VERSION 5.7 ;
BUSBITCHARS "[]" ;
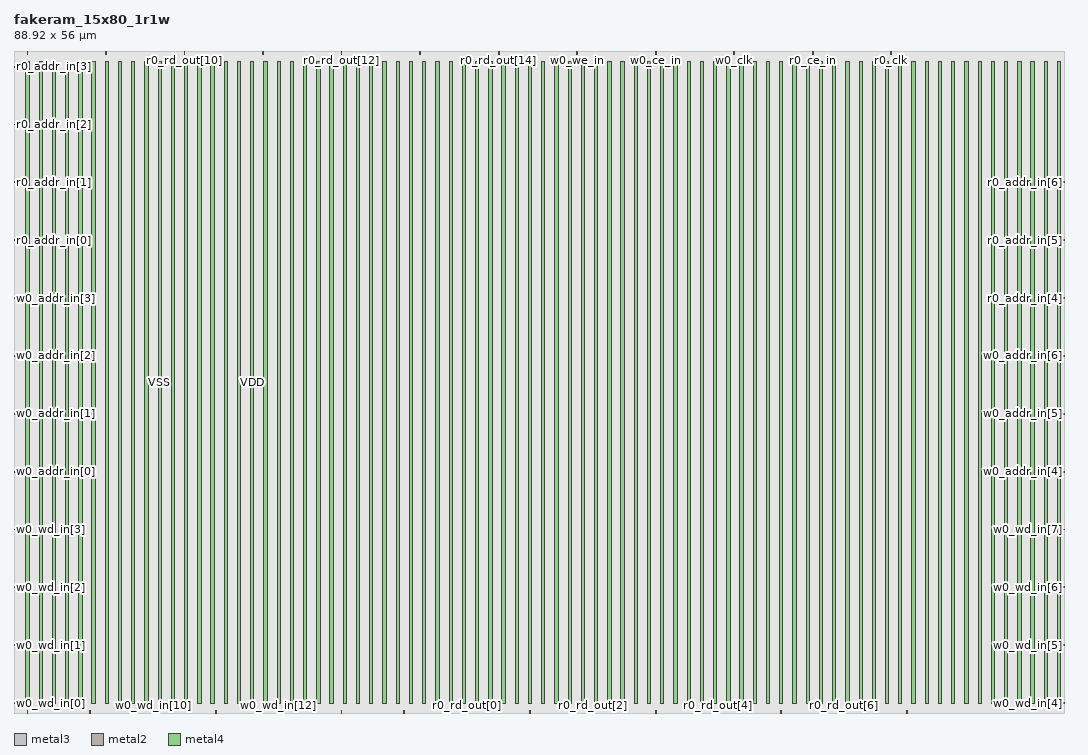
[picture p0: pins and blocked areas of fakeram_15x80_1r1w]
MACRO fakeram_15x80_1r1w
  FOREIGN fakeram_15x80_1r1w 0 0 ;
  SYMMETRY X Y R90 ;
  SIZE 88.920 BY 56.000 ;
  CLASS BLOCK ;
  PIN w0_wd_in[0]
    DIRECTION INPUT ;
    USE SIGNAL ;
    SHAPE ABUTMENT ;
    PORT
      LAYER metal3 ;
      RECT 0.000 0.805 0.210 0.875 ;
    END
  END w0_wd_in[0]
  PIN w0_wd_in[1]
    DIRECTION INPUT ;
    USE SIGNAL ;
    SHAPE ABUTMENT ;
    PORT
      LAYER metal3 ;
      RECT 0.000 5.705 0.210 5.775 ;
    END
  END w0_wd_in[1]
  PIN w0_wd_in[2]
    DIRECTION INPUT ;
    USE SIGNAL ;
    SHAPE ABUTMENT ;
    PORT
      LAYER metal3 ;
      RECT 0.000 10.605 0.210 10.675 ;
    END
  END w0_wd_in[2]
  PIN w0_wd_in[3]
    DIRECTION INPUT ;
    USE SIGNAL ;
    SHAPE ABUTMENT ;
    PORT
      LAYER metal3 ;
      RECT 0.000 15.505 0.210 15.575 ;
    END
  END w0_wd_in[3]
  PIN w0_wd_in[4]
    DIRECTION INPUT ;
    USE SIGNAL ;
    SHAPE ABUTMENT ;
    PORT
      LAYER metal3 ;
      RECT 88.710 0.805 88.920 0.875 ;
    END
  END w0_wd_in[4]
  PIN w0_wd_in[5]
    DIRECTION INPUT ;
    USE SIGNAL ;
    SHAPE ABUTMENT ;
    PORT
      LAYER metal3 ;
      RECT 88.710 5.705 88.920 5.775 ;
    END
  END w0_wd_in[5]
  PIN w0_wd_in[6]
    DIRECTION INPUT ;
    USE SIGNAL ;
    SHAPE ABUTMENT ;
    PORT
      LAYER metal3 ;
      RECT 88.710 10.605 88.920 10.675 ;
    END
  END w0_wd_in[6]
  PIN w0_wd_in[7]
    DIRECTION INPUT ;
    USE SIGNAL ;
    SHAPE ABUTMENT ;
    PORT
      LAYER metal3 ;
      RECT 88.710 15.505 88.920 15.575 ;
    END
  END w0_wd_in[7]
  PIN w0_wd_in[8]
    DIRECTION INPUT ;
    USE SIGNAL ;
    SHAPE ABUTMENT ;
    PORT
      LAYER metal2 ;
      RECT 1.105 0.000 1.175 0.210 ;
    END
  END w0_wd_in[8]
  PIN w0_wd_in[9]
    DIRECTION INPUT ;
    USE SIGNAL ;
    SHAPE ABUTMENT ;
    PORT
      LAYER metal2 ;
      RECT 6.425 0.000 6.495 0.210 ;
    END
  END w0_wd_in[9]
  PIN w0_wd_in[10]
    DIRECTION INPUT ;
    USE SIGNAL ;
    SHAPE ABUTMENT ;
    PORT
      LAYER metal2 ;
      RECT 11.745 0.000 11.815 0.210 ;
    END
  END w0_wd_in[10]
  PIN w0_wd_in[11]
    DIRECTION INPUT ;
    USE SIGNAL ;
    SHAPE ABUTMENT ;
    PORT
      LAYER metal2 ;
      RECT 17.065 0.000 17.135 0.210 ;
    END
  END w0_wd_in[11]
  PIN w0_wd_in[12]
    DIRECTION INPUT ;
    USE SIGNAL ;
    SHAPE ABUTMENT ;
    PORT
      LAYER metal2 ;
      RECT 22.385 0.000 22.455 0.210 ;
    END
  END w0_wd_in[12]
  PIN w0_wd_in[13]
    DIRECTION INPUT ;
    USE SIGNAL ;
    SHAPE ABUTMENT ;
    PORT
      LAYER metal2 ;
      RECT 27.705 0.000 27.775 0.210 ;
    END
  END w0_wd_in[13]
  PIN w0_wd_in[14]
    DIRECTION INPUT ;
    USE SIGNAL ;
    SHAPE ABUTMENT ;
    PORT
      LAYER metal2 ;
      RECT 33.025 0.000 33.095 0.210 ;
    END
  END w0_wd_in[14]
  PIN r0_rd_out[0]
    DIRECTION OUTPUT ;
    USE SIGNAL ;
    SHAPE ABUTMENT ;
    PORT
      LAYER metal2 ;
      RECT 38.345 0.000 38.415 0.210 ;
    END
  END r0_rd_out[0]
  PIN r0_rd_out[1]
    DIRECTION OUTPUT ;
    USE SIGNAL ;
    SHAPE ABUTMENT ;
    PORT
      LAYER metal2 ;
      RECT 43.665 0.000 43.735 0.210 ;
    END
  END r0_rd_out[1]
  PIN r0_rd_out[2]
    DIRECTION OUTPUT ;
    USE SIGNAL ;
    SHAPE ABUTMENT ;
    PORT
      LAYER metal2 ;
      RECT 48.985 0.000 49.055 0.210 ;
    END
  END r0_rd_out[2]
  PIN r0_rd_out[3]
    DIRECTION OUTPUT ;
    USE SIGNAL ;
    SHAPE ABUTMENT ;
    PORT
      LAYER metal2 ;
      RECT 54.305 0.000 54.375 0.210 ;
    END
  END r0_rd_out[3]
  PIN r0_rd_out[4]
    DIRECTION OUTPUT ;
    USE SIGNAL ;
    SHAPE ABUTMENT ;
    PORT
      LAYER metal2 ;
      RECT 59.625 0.000 59.695 0.210 ;
    END
  END r0_rd_out[4]
  PIN r0_rd_out[5]
    DIRECTION OUTPUT ;
    USE SIGNAL ;
    SHAPE ABUTMENT ;
    PORT
      LAYER metal2 ;
      RECT 64.945 0.000 65.015 0.210 ;
    END
  END r0_rd_out[5]
  PIN r0_rd_out[6]
    DIRECTION OUTPUT ;
    USE SIGNAL ;
    SHAPE ABUTMENT ;
    PORT
      LAYER metal2 ;
      RECT 70.265 0.000 70.335 0.210 ;
    END
  END r0_rd_out[6]
  PIN r0_rd_out[7]
    DIRECTION OUTPUT ;
    USE SIGNAL ;
    SHAPE ABUTMENT ;
    PORT
      LAYER metal2 ;
      RECT 75.585 0.000 75.655 0.210 ;
    END
  END r0_rd_out[7]
  PIN r0_rd_out[8]
    DIRECTION OUTPUT ;
    USE SIGNAL ;
    SHAPE ABUTMENT ;
    PORT
      LAYER metal2 ;
      RECT 1.105 55.790 1.175 56.000 ;
    END
  END r0_rd_out[8]
  PIN r0_rd_out[9]
    DIRECTION OUTPUT ;
    USE SIGNAL ;
    SHAPE ABUTMENT ;
    PORT
      LAYER metal2 ;
      RECT 7.755 55.790 7.825 56.000 ;
    END
  END r0_rd_out[9]
  PIN r0_rd_out[10]
    DIRECTION OUTPUT ;
    USE SIGNAL ;
    SHAPE ABUTMENT ;
    PORT
      LAYER metal2 ;
      RECT 14.405 55.790 14.475 56.000 ;
    END
  END r0_rd_out[10]
  PIN r0_rd_out[11]
    DIRECTION OUTPUT ;
    USE SIGNAL ;
    SHAPE ABUTMENT ;
    PORT
      LAYER metal2 ;
      RECT 21.055 55.790 21.125 56.000 ;
    END
  END r0_rd_out[11]
  PIN r0_rd_out[12]
    DIRECTION OUTPUT ;
    USE SIGNAL ;
    SHAPE ABUTMENT ;
    PORT
      LAYER metal2 ;
      RECT 27.705 55.790 27.775 56.000 ;
    END
  END r0_rd_out[12]
  PIN r0_rd_out[13]
    DIRECTION OUTPUT ;
    USE SIGNAL ;
    SHAPE ABUTMENT ;
    PORT
      LAYER metal2 ;
      RECT 34.355 55.790 34.425 56.000 ;
    END
  END r0_rd_out[13]
  PIN r0_rd_out[14]
    DIRECTION OUTPUT ;
    USE SIGNAL ;
    SHAPE ABUTMENT ;
    PORT
      LAYER metal2 ;
      RECT 41.005 55.790 41.075 56.000 ;
    END
  END r0_rd_out[14]
  PIN w0_addr_in[0]
    DIRECTION INPUT ;
    USE SIGNAL ;
    SHAPE ABUTMENT ;
    PORT
      LAYER metal3 ;
      RECT 0.000 20.405 0.210 20.475 ;
    END
  END w0_addr_in[0]
  PIN w0_addr_in[1]
    DIRECTION INPUT ;
    USE SIGNAL ;
    SHAPE ABUTMENT ;
    PORT
      LAYER metal3 ;
      RECT 0.000 25.305 0.210 25.375 ;
    END
  END w0_addr_in[1]
  PIN w0_addr_in[2]
    DIRECTION INPUT ;
    USE SIGNAL ;
    SHAPE ABUTMENT ;
    PORT
      LAYER metal3 ;
      RECT 0.000 30.205 0.210 30.275 ;
    END
  END w0_addr_in[2]
  PIN w0_addr_in[3]
    DIRECTION INPUT ;
    USE SIGNAL ;
    SHAPE ABUTMENT ;
    PORT
      LAYER metal3 ;
      RECT 0.000 35.105 0.210 35.175 ;
    END
  END w0_addr_in[3]
  PIN w0_addr_in[4]
    DIRECTION INPUT ;
    USE SIGNAL ;
    SHAPE ABUTMENT ;
    PORT
      LAYER metal3 ;
      RECT 88.710 20.405 88.920 20.475 ;
    END
  END w0_addr_in[4]
  PIN w0_addr_in[5]
    DIRECTION INPUT ;
    USE SIGNAL ;
    SHAPE ABUTMENT ;
    PORT
      LAYER metal3 ;
      RECT 88.710 25.305 88.920 25.375 ;
    END
  END w0_addr_in[5]
  PIN w0_addr_in[6]
    DIRECTION INPUT ;
    USE SIGNAL ;
    SHAPE ABUTMENT ;
    PORT
      LAYER metal3 ;
      RECT 88.710 30.205 88.920 30.275 ;
    END
  END w0_addr_in[6]
  PIN r0_addr_in[0]
    DIRECTION INPUT ;
    USE SIGNAL ;
    SHAPE ABUTMENT ;
    PORT
      LAYER metal3 ;
      RECT 0.000 40.005 0.210 40.075 ;
    END
  END r0_addr_in[0]
  PIN r0_addr_in[1]
    DIRECTION INPUT ;
    USE SIGNAL ;
    SHAPE ABUTMENT ;
    PORT
      LAYER metal3 ;
      RECT 0.000 44.905 0.210 44.975 ;
    END
  END r0_addr_in[1]
  PIN r0_addr_in[2]
    DIRECTION INPUT ;
    USE SIGNAL ;
    SHAPE ABUTMENT ;
    PORT
      LAYER metal3 ;
      RECT 0.000 49.805 0.210 49.875 ;
    END
  END r0_addr_in[2]
  PIN r0_addr_in[3]
    DIRECTION INPUT ;
    USE SIGNAL ;
    SHAPE ABUTMENT ;
    PORT
      LAYER metal3 ;
      RECT 0.000 54.705 0.210 54.775 ;
    END
  END r0_addr_in[3]
  PIN r0_addr_in[4]
    DIRECTION INPUT ;
    USE SIGNAL ;
    SHAPE ABUTMENT ;
    PORT
      LAYER metal3 ;
      RECT 88.710 35.105 88.920 35.175 ;
    END
  END r0_addr_in[4]
  PIN r0_addr_in[5]
    DIRECTION INPUT ;
    USE SIGNAL ;
    SHAPE ABUTMENT ;
    PORT
      LAYER metal3 ;
      RECT 88.710 40.005 88.920 40.075 ;
    END
  END r0_addr_in[5]
  PIN r0_addr_in[6]
    DIRECTION INPUT ;
    USE SIGNAL ;
    SHAPE ABUTMENT ;
    PORT
      LAYER metal3 ;
      RECT 88.710 44.905 88.920 44.975 ;
    END
  END r0_addr_in[6]
  PIN w0_we_in
    DIRECTION INPUT ;
    USE SIGNAL ;
    SHAPE ABUTMENT ;
    PORT
      LAYER metal2 ;
      RECT 47.655 55.790 47.725 56.000 ;
    END
  END w0_we_in
  PIN w0_ce_in
    DIRECTION INPUT ;
    USE SIGNAL ;
    SHAPE ABUTMENT ;
    PORT
      LAYER metal2 ;
      RECT 54.305 55.790 54.375 56.000 ;
    END
  END w0_ce_in
  PIN w0_clk
    DIRECTION INPUT ;
    USE SIGNAL ;
    SHAPE ABUTMENT ;
    PORT
      LAYER metal2 ;
      RECT 60.955 55.790 61.025 56.000 ;
    END
  END w0_clk
  PIN r0_ce_in
    DIRECTION INPUT ;
    USE SIGNAL ;
    SHAPE ABUTMENT ;
    PORT
      LAYER metal2 ;
      RECT 67.605 55.790 67.675 56.000 ;
    END
  END r0_ce_in
  PIN r0_clk
    DIRECTION INPUT ;
    USE SIGNAL ;
    SHAPE ABUTMENT ;
    PORT
      LAYER metal2 ;
      RECT 74.255 55.790 74.325 56.000 ;
    END
  END r0_clk
  PIN VSS
    DIRECTION INOUT ;
    USE GROUND ;
    PORT
      LAYER metal4 ;
      RECT 1.000 0.840 1.280 55.160 ;
      RECT 3.240 0.840 3.520 55.160 ;
      RECT 5.480 0.840 5.760 55.160 ;
      RECT 7.720 0.840 8.000 55.160 ;
      RECT 9.960 0.840 10.240 55.160 ;
      RECT 12.200 0.840 12.480 55.160 ;
      RECT 14.440 0.840 14.720 55.160 ;
      RECT 16.680 0.840 16.960 55.160 ;
      RECT 18.920 0.840 19.200 55.160 ;
      RECT 21.160 0.840 21.440 55.160 ;
      RECT 23.400 0.840 23.680 55.160 ;
      RECT 25.640 0.840 25.920 55.160 ;
      RECT 27.880 0.840 28.160 55.160 ;
      RECT 30.120 0.840 30.400 55.160 ;
      RECT 32.360 0.840 32.640 55.160 ;
      RECT 34.600 0.840 34.880 55.160 ;
      RECT 36.840 0.840 37.120 55.160 ;
      RECT 39.080 0.840 39.360 55.160 ;
      RECT 41.320 0.840 41.600 55.160 ;
      RECT 43.560 0.840 43.840 55.160 ;
      RECT 45.800 0.840 46.080 55.160 ;
      RECT 48.040 0.840 48.320 55.160 ;
      RECT 50.280 0.840 50.560 55.160 ;
      RECT 52.520 0.840 52.800 55.160 ;
      RECT 54.760 0.840 55.040 55.160 ;
      RECT 57.000 0.840 57.280 55.160 ;
      RECT 59.240 0.840 59.520 55.160 ;
      RECT 61.480 0.840 61.760 55.160 ;
      RECT 63.720 0.840 64.000 55.160 ;
      RECT 65.960 0.840 66.240 55.160 ;
      RECT 68.200 0.840 68.480 55.160 ;
      RECT 70.440 0.840 70.720 55.160 ;
      RECT 72.680 0.840 72.960 55.160 ;
      RECT 74.920 0.840 75.200 55.160 ;
      RECT 77.160 0.840 77.440 55.160 ;
      RECT 79.400 0.840 79.680 55.160 ;
      RECT 81.640 0.840 81.920 55.160 ;
      RECT 83.880 0.840 84.160 55.160 ;
      RECT 86.120 0.840 86.400 55.160 ;
      RECT 88.360 0.840 88.640 55.160 ;
    END
  END VSS
  PIN VDD
    DIRECTION INOUT ;
    USE POWER ;
    PORT
      LAYER metal4 ;
      RECT 2.120 0.840 2.400 55.160 ;
      RECT 4.360 0.840 4.640 55.160 ;
      RECT 6.600 0.840 6.880 55.160 ;
      RECT 8.840 0.840 9.120 55.160 ;
      RECT 11.080 0.840 11.360 55.160 ;
      RECT 13.320 0.840 13.600 55.160 ;
      RECT 15.560 0.840 15.840 55.160 ;
      RECT 17.800 0.840 18.080 55.160 ;
      RECT 20.040 0.840 20.320 55.160 ;
      RECT 22.280 0.840 22.560 55.160 ;
      RECT 24.520 0.840 24.800 55.160 ;
      RECT 26.760 0.840 27.040 55.160 ;
      RECT 29.000 0.840 29.280 55.160 ;
      RECT 31.240 0.840 31.520 55.160 ;
      RECT 33.480 0.840 33.760 55.160 ;
      RECT 35.720 0.840 36.000 55.160 ;
      RECT 37.960 0.840 38.240 55.160 ;
      RECT 40.200 0.840 40.480 55.160 ;
      RECT 42.440 0.840 42.720 55.160 ;
      RECT 44.680 0.840 44.960 55.160 ;
      RECT 46.920 0.840 47.200 55.160 ;
      RECT 49.160 0.840 49.440 55.160 ;
      RECT 51.400 0.840 51.680 55.160 ;
      RECT 53.640 0.840 53.920 55.160 ;
      RECT 55.880 0.840 56.160 55.160 ;
      RECT 58.120 0.840 58.400 55.160 ;
      RECT 60.360 0.840 60.640 55.160 ;
      RECT 62.600 0.840 62.880 55.160 ;
      RECT 64.840 0.840 65.120 55.160 ;
      RECT 67.080 0.840 67.360 55.160 ;
      RECT 69.320 0.840 69.600 55.160 ;
      RECT 71.560 0.840 71.840 55.160 ;
      RECT 73.800 0.840 74.080 55.160 ;
      RECT 76.040 0.840 76.320 55.160 ;
      RECT 78.280 0.840 78.560 55.160 ;
      RECT 80.520 0.840 80.800 55.160 ;
      RECT 82.760 0.840 83.040 55.160 ;
      RECT 85.000 0.840 85.280 55.160 ;
      RECT 87.240 0.840 87.520 55.160 ;
    END
  END VDD
  OBS
    LAYER metal1 ;
    RECT 0 0 88.920 56.000 ;
    LAYER metal2 ;
    RECT 0 0 88.920 56.000 ;
    LAYER metal3 ;
    RECT 0 0 88.920 56.000 ;
    LAYER metal4 ;
    RECT 0 0 88.920 56.000 ;
    LAYER OVERLAP ;
    RECT 0 0 88.920 56.000 ;
  END
END fakeram_15x80_1r1w

END LIBRARY
